VERSION 5.7 ;
  NOWIREEXTENSIONATPIN ON ;
  DIVIDERCHAR "/" ;
  BUSBITCHARS "[]" ;
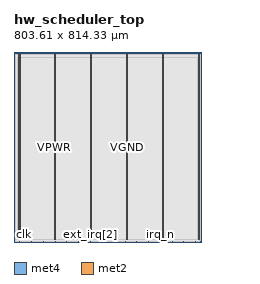
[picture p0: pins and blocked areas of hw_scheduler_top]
MACRO hw_scheduler_top
  CLASS BLOCK ;
  FOREIGN hw_scheduler_top ;
  ORIGIN 0.000 0.000 ;
  SIZE 803.610 BY 814.330 ;
  PIN VGND
    DIRECTION INOUT ;
    USE GROUND ;
    PORT
      LAYER met4 ;
        RECT 24.340 10.640 25.940 802.640 ;
    END
    PORT
      LAYER met4 ;
        RECT 177.940 10.640 179.540 802.640 ;
    END
    PORT
      LAYER met4 ;
        RECT 331.540 10.640 333.140 802.640 ;
    END
    PORT
      LAYER met4 ;
        RECT 485.140 10.640 486.740 802.640 ;
    END
    PORT
      LAYER met4 ;
        RECT 638.740 10.640 640.340 802.640 ;
    END
    PORT
      LAYER met4 ;
        RECT 792.340 10.640 793.940 802.640 ;
    END
  END VGND
  PIN VPWR
    DIRECTION INOUT ;
    USE POWER ;
    PORT
      LAYER met4 ;
        RECT 21.040 10.640 22.640 802.640 ;
    END
    PORT
      LAYER met4 ;
        RECT 174.640 10.640 176.240 802.640 ;
    END
    PORT
      LAYER met4 ;
        RECT 328.240 10.640 329.840 802.640 ;
    END
    PORT
      LAYER met4 ;
        RECT 481.840 10.640 483.440 802.640 ;
    END
    PORT
      LAYER met4 ;
        RECT 635.440 10.640 637.040 802.640 ;
    END
    PORT
      LAYER met4 ;
        RECT 789.040 10.640 790.640 802.640 ;
    END
  END VPWR
  PIN clk
    DIRECTION INPUT ;
    USE SIGNAL ;
    ANTENNAGATEAREA 1.286700 ;
    ANTENNADIFFAREA 0.434700 ;
    PORT
      LAYER met2 ;
        RECT 25.390 0.000 25.670 0.280 ;
    END
  END clk
  PIN ext_irq[0]
    DIRECTION INPUT ;
    USE SIGNAL ;
    ANTENNAGATEAREA 0.560700 ;
    ANTENNADIFFAREA 0.434700 ;
    PORT
      LAYER met2 ;
        RECT 225.950 0.000 226.230 0.280 ;
    END
  END ext_irq[0]
  PIN ext_irq[1]
    DIRECTION INPUT ;
    USE SIGNAL ;
    ANTENNAGATEAREA 0.647700 ;
    ANTENNADIFFAREA 0.434700 ;
    PORT
      LAYER met2 ;
        RECT 276.090 0.000 276.370 0.280 ;
    END
  END ext_irq[1]
  PIN ext_irq[2]
    DIRECTION INPUT ;
    USE SIGNAL ;
    ANTENNAGATEAREA 0.647700 ;
    ANTENNADIFFAREA 0.434700 ;
    PORT
      LAYER met2 ;
        RECT 326.230 0.000 326.510 0.280 ;
    END
  END ext_irq[2]
  PIN ext_irq[3]
    DIRECTION INPUT ;
    USE SIGNAL ;
    ANTENNAGATEAREA 0.647700 ;
    ANTENNADIFFAREA 0.434700 ;
    PORT
      LAYER met2 ;
        RECT 376.370 0.000 376.650 0.280 ;
    END
  END ext_irq[3]
  PIN ext_irq[4]
    DIRECTION INPUT ;
    USE SIGNAL ;
    ANTENNAGATEAREA 0.647700 ;
    ANTENNADIFFAREA 0.434700 ;
    PORT
      LAYER met2 ;
        RECT 426.510 0.000 426.790 0.280 ;
    END
  END ext_irq[4]
  PIN ext_irq[5]
    DIRECTION INPUT ;
    USE SIGNAL ;
    ANTENNAGATEAREA 0.647700 ;
    ANTENNADIFFAREA 0.434700 ;
    PORT
      LAYER met2 ;
        RECT 476.650 0.000 476.930 0.280 ;
    END
  END ext_irq[5]
  PIN ext_irq[6]
    DIRECTION INPUT ;
    USE SIGNAL ;
    ANTENNAGATEAREA 0.560700 ;
    ANTENNADIFFAREA 0.434700 ;
    PORT
      LAYER met2 ;
        RECT 526.790 0.000 527.070 0.280 ;
    END
  END ext_irq[6]
  PIN ext_irq[7]
    DIRECTION INPUT ;
    USE SIGNAL ;
    ANTENNAGATEAREA 0.560700 ;
    ANTENNADIFFAREA 0.434700 ;
    PORT
      LAYER met2 ;
        RECT 576.930 0.000 577.210 0.280 ;
    END
  END ext_irq[7]
  PIN irq_n
    DIRECTION OUTPUT ;
    USE SIGNAL ;
    ANTENNAGATEAREA 0.434700 ;
    ANTENNADIFFAREA 3.107700 ;
    PORT
      LAYER met2 ;
        RECT 627.070 0.000 627.350 0.280 ;
    END
  END irq_n
  PIN rst_n
    DIRECTION INPUT ;
    USE SIGNAL ;
    ANTENNAGATEAREA 0.593700 ;
    ANTENNADIFFAREA 0.434700 ;
    PORT
      LAYER met2 ;
        RECT 75.530 0.000 75.810 0.280 ;
    END
  END rst_n
  PIN scan_en
    DIRECTION INPUT ;
    USE SIGNAL ;
    ANTENNAGATEAREA 228.976196 ;
    ANTENNADIFFAREA 111.283195 ;
    PORT
      LAYER met2 ;
        RECT 677.210 0.000 677.490 0.280 ;
    END
  END scan_en
  PIN scan_in
    DIRECTION INPUT ;
    USE SIGNAL ;
    ANTENNAGATEAREA 0.631200 ;
    ANTENNADIFFAREA 0.434700 ;
    PORT
      LAYER met2 ;
        RECT 727.350 0.000 727.630 0.280 ;
    END
  END scan_in
  PIN scan_out
    DIRECTION OUTPUT ;
    USE SIGNAL ;
    ANTENNAGATEAREA 0.434700 ;
    ANTENNADIFFAREA 3.107700 ;
    PORT
      LAYER met2 ;
        RECT 777.490 0.000 777.770 0.280 ;
    END
  END scan_out
  PIN uart_rx
    DIRECTION INPUT ;
    USE SIGNAL ;
    ANTENNAGATEAREA 0.560700 ;
    ANTENNADIFFAREA 0.434700 ;
    PORT
      LAYER met2 ;
        RECT 125.670 0.000 125.950 0.280 ;
    END
  END uart_rx
  PIN uart_tx
    DIRECTION OUTPUT ;
    USE SIGNAL ;
    ANTENNAGATEAREA 0.434700 ;
    ANTENNADIFFAREA 3.107700 ;
    PORT
      LAYER met2 ;
        RECT 175.810 0.000 176.090 0.280 ;
    END
  END uart_tx
  OBS
      LAYER nwell ;
        RECT 5.330 10.795 797.830 802.590 ;
      LAYER li1 ;
        RECT 5.520 10.795 797.640 802.485 ;
      LAYER met1 ;
        RECT 4.670 6.160 797.640 802.640 ;
      LAYER met2 ;
        RECT 4.700 0.560 797.080 802.585 ;
        RECT 4.700 0.280 25.110 0.560 ;
        RECT 25.950 0.280 75.250 0.560 ;
        RECT 76.090 0.280 125.390 0.560 ;
        RECT 126.230 0.280 175.530 0.560 ;
        RECT 176.370 0.280 225.670 0.560 ;
        RECT 226.510 0.280 275.810 0.560 ;
        RECT 276.650 0.280 325.950 0.560 ;
        RECT 326.790 0.280 376.090 0.560 ;
        RECT 376.930 0.280 426.230 0.560 ;
        RECT 427.070 0.280 476.370 0.560 ;
        RECT 477.210 0.280 526.510 0.560 ;
        RECT 527.350 0.280 576.650 0.560 ;
        RECT 577.490 0.280 626.790 0.560 ;
        RECT 627.630 0.280 676.930 0.560 ;
        RECT 677.770 0.280 727.070 0.560 ;
        RECT 727.910 0.280 777.210 0.560 ;
        RECT 778.050 0.280 797.080 0.560 ;
      LAYER met3 ;
        RECT 5.125 10.715 793.930 802.565 ;
      LAYER met4 ;
        RECT 13.175 11.735 20.640 791.345 ;
        RECT 23.040 11.735 23.940 791.345 ;
        RECT 26.340 11.735 174.240 791.345 ;
        RECT 176.640 11.735 177.540 791.345 ;
        RECT 179.940 11.735 327.840 791.345 ;
        RECT 330.240 11.735 331.140 791.345 ;
        RECT 333.540 11.735 481.440 791.345 ;
        RECT 483.840 11.735 484.740 791.345 ;
        RECT 487.140 11.735 635.040 791.345 ;
        RECT 637.440 11.735 638.340 791.345 ;
        RECT 640.740 11.735 788.145 791.345 ;
  END
END hw_scheduler_top
END LIBRARY

